###############################################################
#  Generated by:      Cadence Innovus 21.13-s100_1
#  OS:                Linux x86_64(Host ID acf3030)
#  Generated on:      Thu Oct 27 19:12:06 2022
#  Design:            b14
#  Command:           write_lef_abstract ./pnr_out/b14.pnr.lef
###############################################################

VERSION 5.8 ;

BUSBITCHARS "[]" ;
DIVIDERCHAR "/" ;

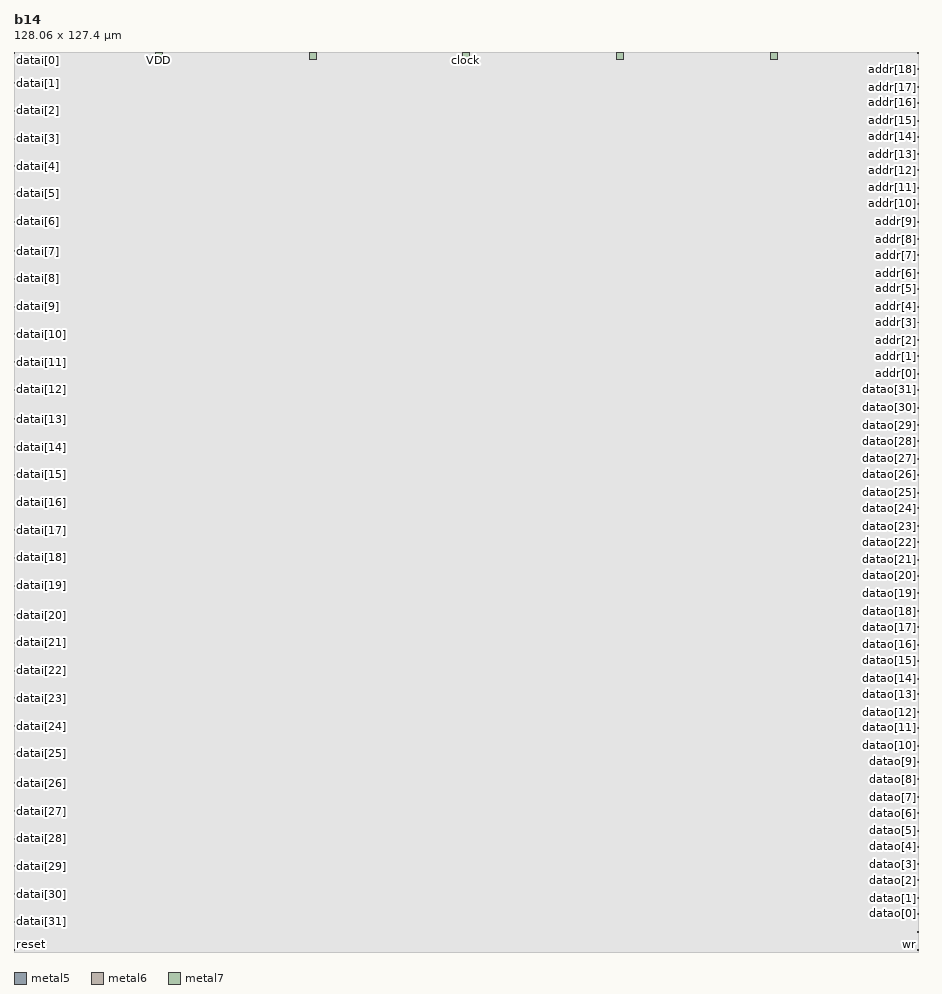
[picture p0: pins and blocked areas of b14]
MACRO b14
  CLASS BLOCK ;
  SIZE 128.060000 BY 127.400000 ;
  FOREIGN b14 0.000000 0.000000 ;
  ORIGIN 0 0 ;
  SYMMETRY X Y R90 ;
  PIN clock
    DIRECTION INPUT ;
    USE CLOCK ;
    PORT
      LAYER metal5 ;
        RECT 63.865000 127.260000 64.005000 127.400000 ;
    END
  END clock
  PIN reset
    DIRECTION INPUT ;
    USE SIGNAL ;
    PORT
      LAYER metal6 ;
        RECT 0.000000 0.280000 0.140000 0.420000 ;
    END
  END reset
  PIN addr[19]
    DIRECTION OUTPUT ;
    USE SIGNAL ;
    PORT
      LAYER metal6 ;
        RECT 127.920000 127.120000 128.060000 127.260000 ;
    END
  END addr[19]
  PIN addr[18]
    DIRECTION OUTPUT ;
    USE SIGNAL ;
    PORT
      LAYER metal6 ;
        RECT 127.920000 124.880000 128.060000 125.020000 ;
    END
  END addr[18]
  PIN addr[17]
    DIRECTION OUTPUT ;
    USE SIGNAL ;
    PORT
      LAYER metal6 ;
        RECT 127.920000 122.360000 128.060000 122.500000 ;
    END
  END addr[17]
  PIN addr[16]
    DIRECTION OUTPUT ;
    USE SIGNAL ;
    PORT
      LAYER metal6 ;
        RECT 127.920000 120.120000 128.060000 120.260000 ;
    END
  END addr[16]
  PIN addr[15]
    DIRECTION OUTPUT ;
    USE SIGNAL ;
    PORT
      LAYER metal6 ;
        RECT 127.920000 117.600000 128.060000 117.740000 ;
    END
  END addr[15]
  PIN addr[14]
    DIRECTION OUTPUT ;
    USE SIGNAL ;
    PORT
      LAYER metal6 ;
        RECT 127.920000 115.360000 128.060000 115.500000 ;
    END
  END addr[14]
  PIN addr[13]
    DIRECTION OUTPUT ;
    USE SIGNAL ;
    PORT
      LAYER metal6 ;
        RECT 127.920000 112.840000 128.060000 112.980000 ;
    END
  END addr[13]
  PIN addr[12]
    DIRECTION OUTPUT ;
    USE SIGNAL ;
    PORT
      LAYER metal6 ;
        RECT 127.920000 110.600000 128.060000 110.740000 ;
    END
  END addr[12]
  PIN addr[11]
    DIRECTION OUTPUT ;
    USE SIGNAL ;
    PORT
      LAYER metal6 ;
        RECT 127.920000 108.080000 128.060000 108.220000 ;
    END
  END addr[11]
  PIN addr[10]
    DIRECTION OUTPUT ;
    USE SIGNAL ;
    PORT
      LAYER metal6 ;
        RECT 127.920000 105.840000 128.060000 105.980000 ;
    END
  END addr[10]
  PIN addr[9]
    DIRECTION OUTPUT ;
    USE SIGNAL ;
    PORT
      LAYER metal6 ;
        RECT 127.920000 103.320000 128.060000 103.460000 ;
    END
  END addr[9]
  PIN addr[8]
    DIRECTION OUTPUT ;
    USE SIGNAL ;
    PORT
      LAYER metal6 ;
        RECT 127.920000 100.800000 128.060000 100.940000 ;
    END
  END addr[8]
  PIN addr[7]
    DIRECTION OUTPUT ;
    USE SIGNAL ;
    PORT
      LAYER metal6 ;
        RECT 127.920000 98.560000 128.060000 98.700000 ;
    END
  END addr[7]
  PIN addr[6]
    DIRECTION OUTPUT ;
    USE SIGNAL ;
    PORT
      LAYER metal6 ;
        RECT 127.920000 96.040000 128.060000 96.180000 ;
    END
  END addr[6]
  PIN addr[5]
    DIRECTION OUTPUT ;
    USE SIGNAL ;
    PORT
      LAYER metal6 ;
        RECT 127.920000 93.800000 128.060000 93.940000 ;
    END
  END addr[5]
  PIN addr[4]
    DIRECTION OUTPUT ;
    USE SIGNAL ;
    PORT
      LAYER metal6 ;
        RECT 127.920000 91.280000 128.060000 91.420000 ;
    END
  END addr[4]
  PIN addr[3]
    DIRECTION OUTPUT ;
    USE SIGNAL ;
    PORT
      LAYER metal6 ;
        RECT 127.920000 89.040000 128.060000 89.180000 ;
    END
  END addr[3]
  PIN addr[2]
    DIRECTION OUTPUT ;
    USE SIGNAL ;
    PORT
      LAYER metal6 ;
        RECT 127.920000 86.520000 128.060000 86.660000 ;
    END
  END addr[2]
  PIN addr[1]
    DIRECTION OUTPUT ;
    USE SIGNAL ;
    PORT
      LAYER metal6 ;
        RECT 127.920000 84.280000 128.060000 84.420000 ;
    END
  END addr[1]
  PIN addr[0]
    DIRECTION OUTPUT ;
    USE SIGNAL ;
    PORT
      LAYER metal6 ;
        RECT 127.920000 81.760000 128.060000 81.900000 ;
    END
  END addr[0]
  PIN datai[31]
    DIRECTION INPUT ;
    USE SIGNAL ;
    PORT
      LAYER metal6 ;
        RECT 0.000000 4.200000 0.140000 4.340000 ;
    END
  END datai[31]
  PIN datai[30]
    DIRECTION INPUT ;
    USE SIGNAL ;
    PORT
      LAYER metal6 ;
        RECT 0.000000 8.120000 0.140000 8.260000 ;
    END
  END datai[30]
  PIN datai[29]
    DIRECTION INPUT ;
    USE SIGNAL ;
    PORT
      LAYER metal6 ;
        RECT 0.000000 12.040000 0.140000 12.180000 ;
    END
  END datai[29]
  PIN datai[28]
    DIRECTION INPUT ;
    USE SIGNAL ;
    PORT
      LAYER metal6 ;
        RECT 0.000000 15.960000 0.140000 16.100000 ;
    END
  END datai[28]
  PIN datai[27]
    DIRECTION INPUT ;
    USE SIGNAL ;
    PORT
      LAYER metal6 ;
        RECT 0.000000 19.880000 0.140000 20.020000 ;
    END
  END datai[27]
  PIN datai[26]
    DIRECTION INPUT ;
    USE SIGNAL ;
    PORT
      LAYER metal6 ;
        RECT 0.000000 23.800000 0.140000 23.940000 ;
    END
  END datai[26]
  PIN datai[25]
    DIRECTION INPUT ;
    USE SIGNAL ;
    PORT
      LAYER metal6 ;
        RECT 0.000000 28.000000 0.140000 28.140000 ;
    END
  END datai[25]
  PIN datai[24]
    DIRECTION INPUT ;
    USE SIGNAL ;
    PORT
      LAYER metal6 ;
        RECT 0.000000 31.920000 0.140000 32.060000 ;
    END
  END datai[24]
  PIN datai[23]
    DIRECTION INPUT ;
    USE SIGNAL ;
    PORT
      LAYER metal6 ;
        RECT 0.000000 35.840000 0.140000 35.980000 ;
    END
  END datai[23]
  PIN datai[22]
    DIRECTION INPUT ;
    USE SIGNAL ;
    PORT
      LAYER metal6 ;
        RECT 0.000000 39.760000 0.140000 39.900000 ;
    END
  END datai[22]
  PIN datai[21]
    DIRECTION INPUT ;
    USE SIGNAL ;
    PORT
      LAYER metal6 ;
        RECT 0.000000 43.680000 0.140000 43.820000 ;
    END
  END datai[21]
  PIN datai[20]
    DIRECTION INPUT ;
    USE SIGNAL ;
    PORT
      LAYER metal6 ;
        RECT 0.000000 47.600000 0.140000 47.740000 ;
    END
  END datai[20]
  PIN datai[19]
    DIRECTION INPUT ;
    USE SIGNAL ;
    PORT
      LAYER metal6 ;
        RECT 0.000000 51.800000 0.140000 51.940000 ;
    END
  END datai[19]
  PIN datai[18]
    DIRECTION INPUT ;
    USE SIGNAL ;
    PORT
      LAYER metal6 ;
        RECT 0.000000 55.720000 0.140000 55.860000 ;
    END
  END datai[18]
  PIN datai[17]
    DIRECTION INPUT ;
    USE SIGNAL ;
    PORT
      LAYER metal6 ;
        RECT 0.000000 59.640000 0.140000 59.780000 ;
    END
  END datai[17]
  PIN datai[16]
    DIRECTION INPUT ;
    USE SIGNAL ;
    PORT
      LAYER metal6 ;
        RECT 0.000000 63.560000 0.140000 63.700000 ;
    END
  END datai[16]
  PIN datai[15]
    DIRECTION INPUT ;
    USE SIGNAL ;
    PORT
      LAYER metal6 ;
        RECT 0.000000 67.480000 0.140000 67.620000 ;
    END
  END datai[15]
  PIN datai[14]
    DIRECTION INPUT ;
    USE SIGNAL ;
    PORT
      LAYER metal6 ;
        RECT 0.000000 71.400000 0.140000 71.540000 ;
    END
  END datai[14]
  PIN datai[13]
    DIRECTION INPUT ;
    USE SIGNAL ;
    PORT
      LAYER metal6 ;
        RECT 0.000000 75.320000 0.140000 75.460000 ;
    END
  END datai[13]
  PIN datai[12]
    DIRECTION INPUT ;
    USE SIGNAL ;
    PORT
      LAYER metal6 ;
        RECT 0.000000 79.520000 0.140000 79.660000 ;
    END
  END datai[12]
  PIN datai[11]
    DIRECTION INPUT ;
    USE SIGNAL ;
    PORT
      LAYER metal6 ;
        RECT 0.000000 83.440000 0.140000 83.580000 ;
    END
  END datai[11]
  PIN datai[10]
    DIRECTION INPUT ;
    USE SIGNAL ;
    PORT
      LAYER metal6 ;
        RECT 0.000000 87.360000 0.140000 87.500000 ;
    END
  END datai[10]
  PIN datai[9]
    DIRECTION INPUT ;
    USE SIGNAL ;
    PORT
      LAYER metal6 ;
        RECT 0.000000 91.280000 0.140000 91.420000 ;
    END
  END datai[9]
  PIN datai[8]
    DIRECTION INPUT ;
    USE SIGNAL ;
    PORT
      LAYER metal6 ;
        RECT 0.000000 95.200000 0.140000 95.340000 ;
    END
  END datai[8]
  PIN datai[7]
    DIRECTION INPUT ;
    USE SIGNAL ;
    PORT
      LAYER metal6 ;
        RECT 0.000000 99.120000 0.140000 99.260000 ;
    END
  END datai[7]
  PIN datai[6]
    DIRECTION INPUT ;
    USE SIGNAL ;
    PORT
      LAYER metal6 ;
        RECT 0.000000 103.320000 0.140000 103.460000 ;
    END
  END datai[6]
  PIN datai[5]
    DIRECTION INPUT ;
    USE SIGNAL ;
    PORT
      LAYER metal6 ;
        RECT 0.000000 107.240000 0.140000 107.380000 ;
    END
  END datai[5]
  PIN datai[4]
    DIRECTION INPUT ;
    USE SIGNAL ;
    PORT
      LAYER metal6 ;
        RECT 0.000000 111.160000 0.140000 111.300000 ;
    END
  END datai[4]
  PIN datai[3]
    DIRECTION INPUT ;
    USE SIGNAL ;
    PORT
      LAYER metal6 ;
        RECT 0.000000 115.080000 0.140000 115.220000 ;
    END
  END datai[3]
  PIN datai[2]
    DIRECTION INPUT ;
    USE SIGNAL ;
    PORT
      LAYER metal6 ;
        RECT 0.000000 119.000000 0.140000 119.140000 ;
    END
  END datai[2]
  PIN datai[1]
    DIRECTION INPUT ;
    USE SIGNAL ;
    PORT
      LAYER metal6 ;
        RECT 0.000000 122.920000 0.140000 123.060000 ;
    END
  END datai[1]
  PIN datai[0]
    DIRECTION INPUT ;
    USE SIGNAL ;
    PORT
      LAYER metal6 ;
        RECT 0.000000 127.120000 0.140000 127.260000 ;
    END
  END datai[0]
  PIN datao[31]
    DIRECTION OUTPUT ;
    USE SIGNAL ;
    PORT
      LAYER metal6 ;
        RECT 127.920000 79.520000 128.060000 79.660000 ;
    END
  END datao[31]
  PIN datao[30]
    DIRECTION OUTPUT ;
    USE SIGNAL ;
    PORT
      LAYER metal6 ;
        RECT 127.920000 77.000000 128.060000 77.140000 ;
    END
  END datao[30]
  PIN datao[29]
    DIRECTION OUTPUT ;
    USE SIGNAL ;
    PORT
      LAYER metal6 ;
        RECT 127.920000 74.480000 128.060000 74.620000 ;
    END
  END datao[29]
  PIN datao[28]
    DIRECTION OUTPUT ;
    USE SIGNAL ;
    PORT
      LAYER metal6 ;
        RECT 127.920000 72.240000 128.060000 72.380000 ;
    END
  END datao[28]
  PIN datao[27]
    DIRECTION OUTPUT ;
    USE SIGNAL ;
    PORT
      LAYER metal6 ;
        RECT 127.920000 69.720000 128.060000 69.860000 ;
    END
  END datao[27]
  PIN datao[26]
    DIRECTION OUTPUT ;
    USE SIGNAL ;
    PORT
      LAYER metal6 ;
        RECT 127.920000 67.480000 128.060000 67.620000 ;
    END
  END datao[26]
  PIN datao[25]
    DIRECTION OUTPUT ;
    USE SIGNAL ;
    PORT
      LAYER metal6 ;
        RECT 127.920000 64.960000 128.060000 65.100000 ;
    END
  END datao[25]
  PIN datao[24]
    DIRECTION OUTPUT ;
    USE SIGNAL ;
    PORT
      LAYER metal6 ;
        RECT 127.920000 62.720000 128.060000 62.860000 ;
    END
  END datao[24]
  PIN datao[23]
    DIRECTION OUTPUT ;
    USE SIGNAL ;
    PORT
      LAYER metal6 ;
        RECT 127.920000 60.200000 128.060000 60.340000 ;
    END
  END datao[23]
  PIN datao[22]
    DIRECTION OUTPUT ;
    USE SIGNAL ;
    PORT
      LAYER metal6 ;
        RECT 127.920000 57.960000 128.060000 58.100000 ;
    END
  END datao[22]
  PIN datao[21]
    DIRECTION OUTPUT ;
    USE SIGNAL ;
    PORT
      LAYER metal6 ;
        RECT 127.920000 55.440000 128.060000 55.580000 ;
    END
  END datao[21]
  PIN datao[20]
    DIRECTION OUTPUT ;
    USE SIGNAL ;
    PORT
      LAYER metal6 ;
        RECT 127.920000 53.200000 128.060000 53.340000 ;
    END
  END datao[20]
  PIN datao[19]
    DIRECTION OUTPUT ;
    USE SIGNAL ;
    PORT
      LAYER metal6 ;
        RECT 127.920000 50.680000 128.060000 50.820000 ;
    END
  END datao[19]
  PIN datao[18]
    DIRECTION OUTPUT ;
    USE SIGNAL ;
    PORT
      LAYER metal6 ;
        RECT 127.920000 48.160000 128.060000 48.300000 ;
    END
  END datao[18]
  PIN datao[17]
    DIRECTION OUTPUT ;
    USE SIGNAL ;
    PORT
      LAYER metal6 ;
        RECT 127.920000 45.920000 128.060000 46.060000 ;
    END
  END datao[17]
  PIN datao[16]
    DIRECTION OUTPUT ;
    USE SIGNAL ;
    PORT
      LAYER metal6 ;
        RECT 127.920000 43.400000 128.060000 43.540000 ;
    END
  END datao[16]
  PIN datao[15]
    DIRECTION OUTPUT ;
    USE SIGNAL ;
    PORT
      LAYER metal6 ;
        RECT 127.920000 41.160000 128.060000 41.300000 ;
    END
  END datao[15]
  PIN datao[14]
    DIRECTION OUTPUT ;
    USE SIGNAL ;
    PORT
      LAYER metal6 ;
        RECT 127.920000 38.640000 128.060000 38.780000 ;
    END
  END datao[14]
  PIN datao[13]
    DIRECTION OUTPUT ;
    USE SIGNAL ;
    PORT
      LAYER metal6 ;
        RECT 127.920000 36.400000 128.060000 36.540000 ;
    END
  END datao[13]
  PIN datao[12]
    DIRECTION OUTPUT ;
    USE SIGNAL ;
    PORT
      LAYER metal6 ;
        RECT 127.920000 33.880000 128.060000 34.020000 ;
    END
  END datao[12]
  PIN datao[11]
    DIRECTION OUTPUT ;
    USE SIGNAL ;
    PORT
      LAYER metal6 ;
        RECT 127.920000 31.640000 128.060000 31.780000 ;
    END
  END datao[11]
  PIN datao[10]
    DIRECTION OUTPUT ;
    USE SIGNAL ;
    PORT
      LAYER metal6 ;
        RECT 127.920000 29.120000 128.060000 29.260000 ;
    END
  END datao[10]
  PIN datao[9]
    DIRECTION OUTPUT ;
    USE SIGNAL ;
    PORT
      LAYER metal6 ;
        RECT 127.920000 26.880000 128.060000 27.020000 ;
    END
  END datao[9]
  PIN datao[8]
    DIRECTION OUTPUT ;
    USE SIGNAL ;
    PORT
      LAYER metal6 ;
        RECT 127.920000 24.360000 128.060000 24.500000 ;
    END
  END datao[8]
  PIN datao[7]
    DIRECTION OUTPUT ;
    USE SIGNAL ;
    PORT
      LAYER metal6 ;
        RECT 127.920000 21.840000 128.060000 21.980000 ;
    END
  END datao[7]
  PIN datao[6]
    DIRECTION OUTPUT ;
    USE SIGNAL ;
    PORT
      LAYER metal6 ;
        RECT 127.920000 19.600000 128.060000 19.740000 ;
    END
  END datao[6]
  PIN datao[5]
    DIRECTION OUTPUT ;
    USE SIGNAL ;
    PORT
      LAYER metal6 ;
        RECT 127.920000 17.080000 128.060000 17.220000 ;
    END
  END datao[5]
  PIN datao[4]
    DIRECTION OUTPUT ;
    USE SIGNAL ;
    PORT
      LAYER metal6 ;
        RECT 127.920000 14.840000 128.060000 14.980000 ;
    END
  END datao[4]
  PIN datao[3]
    DIRECTION OUTPUT ;
    USE SIGNAL ;
    PORT
      LAYER metal6 ;
        RECT 127.920000 12.320000 128.060000 12.460000 ;
    END
  END datao[3]
  PIN datao[2]
    DIRECTION OUTPUT ;
    USE SIGNAL ;
    PORT
      LAYER metal6 ;
        RECT 127.920000 10.080000 128.060000 10.220000 ;
    END
  END datao[2]
  PIN datao[1]
    DIRECTION OUTPUT ;
    USE SIGNAL ;
    PORT
      LAYER metal6 ;
        RECT 127.920000 7.560000 128.060000 7.700000 ;
    END
  END datao[1]
  PIN datao[0]
    DIRECTION OUTPUT ;
    USE SIGNAL ;
    PORT
      LAYER metal6 ;
        RECT 127.920000 5.320000 128.060000 5.460000 ;
    END
  END datao[0]
  PIN rd
    DIRECTION OUTPUT ;
    USE SIGNAL ;
    PORT
      LAYER metal6 ;
        RECT 127.920000 2.800000 128.060000 2.940000 ;
    END
  END rd
  PIN wr
    DIRECTION OUTPUT ;
    USE SIGNAL ;
    PORT
      LAYER metal6 ;
        RECT 127.920000 0.280000 128.060000 0.420000 ;
    END
  END wr
  PIN VDD
    DIRECTION INOUT ;
    USE POWER ;
    PORT
      LAYER metal7 ;
        RECT 20.000000 126.400000 21.000000 127.400000 ;
    END
    PORT
      LAYER metal7 ;
        RECT 41.765000 126.400000 42.765000 127.400000 ;
    END
    PORT
      LAYER metal7 ;
        RECT 63.530000 126.400000 64.530000 127.400000 ;
    END
    PORT
      LAYER metal7 ;
        RECT 85.295000 126.400000 86.295000 127.400000 ;
    END
    PORT
      LAYER metal7 ;
        RECT 107.060000 126.400000 108.060000 127.400000 ;
    END
  END VDD
  OBS
    LAYER metal1 ;
      RECT 0.000000 0.000000 128.060000 127.400000 ;
    LAYER metal2 ;
      RECT 0.000000 0.000000 128.060000 127.400000 ;
    LAYER metal3 ;
      RECT 0.000000 0.000000 128.060000 127.400000 ;
    LAYER metal4 ;
      RECT 0.000000 0.000000 128.060000 127.400000 ;
    LAYER metal5 ;
      RECT 64.145000 127.120000 128.060000 127.400000 ;
      RECT 0.000000 127.120000 63.725000 127.400000 ;
      RECT 0.000000 0.000000 128.060000 127.120000 ;
    LAYER metal6 ;
      RECT 0.280000 126.980000 127.780000 127.400000 ;
      RECT 0.000000 125.160000 128.060000 126.980000 ;
      RECT 0.000000 124.740000 127.780000 125.160000 ;
      RECT 0.000000 123.200000 128.060000 124.740000 ;
      RECT 0.280000 122.780000 128.060000 123.200000 ;
      RECT 0.000000 122.640000 128.060000 122.780000 ;
      RECT 0.000000 122.220000 127.780000 122.640000 ;
      RECT 0.000000 120.400000 128.060000 122.220000 ;
      RECT 0.000000 119.980000 127.780000 120.400000 ;
      RECT 0.000000 119.280000 128.060000 119.980000 ;
      RECT 0.280000 118.860000 128.060000 119.280000 ;
      RECT 0.000000 117.880000 128.060000 118.860000 ;
      RECT 0.000000 117.460000 127.780000 117.880000 ;
      RECT 0.000000 115.640000 128.060000 117.460000 ;
      RECT 0.000000 115.360000 127.780000 115.640000 ;
      RECT 0.280000 115.220000 127.780000 115.360000 ;
      RECT 0.280000 114.940000 128.060000 115.220000 ;
      RECT 0.000000 113.120000 128.060000 114.940000 ;
      RECT 0.000000 112.700000 127.780000 113.120000 ;
      RECT 0.000000 111.440000 128.060000 112.700000 ;
      RECT 0.280000 111.020000 128.060000 111.440000 ;
      RECT 0.000000 110.880000 128.060000 111.020000 ;
      RECT 0.000000 110.460000 127.780000 110.880000 ;
      RECT 0.000000 108.360000 128.060000 110.460000 ;
      RECT 0.000000 107.940000 127.780000 108.360000 ;
      RECT 0.000000 107.520000 128.060000 107.940000 ;
      RECT 0.280000 107.100000 128.060000 107.520000 ;
      RECT 0.000000 106.120000 128.060000 107.100000 ;
      RECT 0.000000 105.700000 127.780000 106.120000 ;
      RECT 0.000000 103.600000 128.060000 105.700000 ;
      RECT 0.280000 103.180000 127.780000 103.600000 ;
      RECT 0.000000 101.080000 128.060000 103.180000 ;
      RECT 0.000000 100.660000 127.780000 101.080000 ;
      RECT 0.000000 99.400000 128.060000 100.660000 ;
      RECT 0.280000 98.980000 128.060000 99.400000 ;
      RECT 0.000000 98.840000 128.060000 98.980000 ;
      RECT 0.000000 98.420000 127.780000 98.840000 ;
      RECT 0.000000 96.320000 128.060000 98.420000 ;
      RECT 0.000000 95.900000 127.780000 96.320000 ;
      RECT 0.000000 95.480000 128.060000 95.900000 ;
      RECT 0.280000 95.060000 128.060000 95.480000 ;
      RECT 0.000000 94.080000 128.060000 95.060000 ;
      RECT 0.000000 93.660000 127.780000 94.080000 ;
      RECT 0.000000 91.560000 128.060000 93.660000 ;
      RECT 0.280000 91.140000 127.780000 91.560000 ;
      RECT 0.000000 89.320000 128.060000 91.140000 ;
      RECT 0.000000 88.900000 127.780000 89.320000 ;
      RECT 0.000000 87.640000 128.060000 88.900000 ;
      RECT 0.280000 87.220000 128.060000 87.640000 ;
      RECT 0.000000 86.800000 128.060000 87.220000 ;
      RECT 0.000000 86.380000 127.780000 86.800000 ;
      RECT 0.000000 84.560000 128.060000 86.380000 ;
      RECT 0.000000 84.140000 127.780000 84.560000 ;
      RECT 0.000000 83.720000 128.060000 84.140000 ;
      RECT 0.280000 83.300000 128.060000 83.720000 ;
      RECT 0.000000 82.040000 128.060000 83.300000 ;
      RECT 0.000000 81.620000 127.780000 82.040000 ;
      RECT 0.000000 79.800000 128.060000 81.620000 ;
      RECT 0.280000 79.380000 127.780000 79.800000 ;
      RECT 0.000000 77.280000 128.060000 79.380000 ;
      RECT 0.000000 76.860000 127.780000 77.280000 ;
      RECT 0.000000 75.600000 128.060000 76.860000 ;
      RECT 0.280000 75.180000 128.060000 75.600000 ;
      RECT 0.000000 74.760000 128.060000 75.180000 ;
      RECT 0.000000 74.340000 127.780000 74.760000 ;
      RECT 0.000000 72.520000 128.060000 74.340000 ;
      RECT 0.000000 72.100000 127.780000 72.520000 ;
      RECT 0.000000 71.680000 128.060000 72.100000 ;
      RECT 0.280000 71.260000 128.060000 71.680000 ;
      RECT 0.000000 70.000000 128.060000 71.260000 ;
      RECT 0.000000 69.580000 127.780000 70.000000 ;
      RECT 0.000000 67.760000 128.060000 69.580000 ;
      RECT 0.280000 67.340000 127.780000 67.760000 ;
      RECT 0.000000 65.240000 128.060000 67.340000 ;
      RECT 0.000000 64.820000 127.780000 65.240000 ;
      RECT 0.000000 63.840000 128.060000 64.820000 ;
      RECT 0.280000 63.420000 128.060000 63.840000 ;
      RECT 0.000000 63.000000 128.060000 63.420000 ;
      RECT 0.000000 62.580000 127.780000 63.000000 ;
      RECT 0.000000 60.480000 128.060000 62.580000 ;
      RECT 0.000000 60.060000 127.780000 60.480000 ;
      RECT 0.000000 59.920000 128.060000 60.060000 ;
      RECT 0.280000 59.500000 128.060000 59.920000 ;
      RECT 0.000000 58.240000 128.060000 59.500000 ;
      RECT 0.000000 57.820000 127.780000 58.240000 ;
      RECT 0.000000 56.000000 128.060000 57.820000 ;
      RECT 0.280000 55.720000 128.060000 56.000000 ;
      RECT 0.280000 55.580000 127.780000 55.720000 ;
      RECT 0.000000 55.300000 127.780000 55.580000 ;
      RECT 0.000000 53.480000 128.060000 55.300000 ;
      RECT 0.000000 53.060000 127.780000 53.480000 ;
      RECT 0.000000 52.080000 128.060000 53.060000 ;
      RECT 0.280000 51.660000 128.060000 52.080000 ;
      RECT 0.000000 50.960000 128.060000 51.660000 ;
      RECT 0.000000 50.540000 127.780000 50.960000 ;
      RECT 0.000000 48.440000 128.060000 50.540000 ;
      RECT 0.000000 48.020000 127.780000 48.440000 ;
      RECT 0.000000 47.880000 128.060000 48.020000 ;
      RECT 0.280000 47.460000 128.060000 47.880000 ;
      RECT 0.000000 46.200000 128.060000 47.460000 ;
      RECT 0.000000 45.780000 127.780000 46.200000 ;
      RECT 0.000000 43.960000 128.060000 45.780000 ;
      RECT 0.280000 43.680000 128.060000 43.960000 ;
      RECT 0.280000 43.540000 127.780000 43.680000 ;
      RECT 0.000000 43.260000 127.780000 43.540000 ;
      RECT 0.000000 41.440000 128.060000 43.260000 ;
      RECT 0.000000 41.020000 127.780000 41.440000 ;
      RECT 0.000000 40.040000 128.060000 41.020000 ;
      RECT 0.280000 39.620000 128.060000 40.040000 ;
      RECT 0.000000 38.920000 128.060000 39.620000 ;
      RECT 0.000000 38.500000 127.780000 38.920000 ;
      RECT 0.000000 36.680000 128.060000 38.500000 ;
      RECT 0.000000 36.260000 127.780000 36.680000 ;
      RECT 0.000000 36.120000 128.060000 36.260000 ;
      RECT 0.280000 35.700000 128.060000 36.120000 ;
      RECT 0.000000 34.160000 128.060000 35.700000 ;
      RECT 0.000000 33.740000 127.780000 34.160000 ;
      RECT 0.000000 32.200000 128.060000 33.740000 ;
      RECT 0.280000 31.920000 128.060000 32.200000 ;
      RECT 0.280000 31.780000 127.780000 31.920000 ;
      RECT 0.000000 31.500000 127.780000 31.780000 ;
      RECT 0.000000 29.400000 128.060000 31.500000 ;
      RECT 0.000000 28.980000 127.780000 29.400000 ;
      RECT 0.000000 28.280000 128.060000 28.980000 ;
      RECT 0.280000 27.860000 128.060000 28.280000 ;
      RECT 0.000000 27.160000 128.060000 27.860000 ;
      RECT 0.000000 26.740000 127.780000 27.160000 ;
      RECT 0.000000 24.640000 128.060000 26.740000 ;
      RECT 0.000000 24.220000 127.780000 24.640000 ;
      RECT 0.000000 24.080000 128.060000 24.220000 ;
      RECT 0.280000 23.660000 128.060000 24.080000 ;
      RECT 0.000000 22.120000 128.060000 23.660000 ;
      RECT 0.000000 21.700000 127.780000 22.120000 ;
      RECT 0.000000 20.160000 128.060000 21.700000 ;
      RECT 0.280000 19.880000 128.060000 20.160000 ;
      RECT 0.280000 19.740000 127.780000 19.880000 ;
      RECT 0.000000 19.460000 127.780000 19.740000 ;
      RECT 0.000000 17.360000 128.060000 19.460000 ;
      RECT 0.000000 16.940000 127.780000 17.360000 ;
      RECT 0.000000 16.240000 128.060000 16.940000 ;
      RECT 0.280000 15.820000 128.060000 16.240000 ;
      RECT 0.000000 15.120000 128.060000 15.820000 ;
      RECT 0.000000 14.700000 127.780000 15.120000 ;
      RECT 0.000000 12.600000 128.060000 14.700000 ;
      RECT 0.000000 12.320000 127.780000 12.600000 ;
      RECT 0.280000 12.180000 127.780000 12.320000 ;
      RECT 0.280000 11.900000 128.060000 12.180000 ;
      RECT 0.000000 10.360000 128.060000 11.900000 ;
      RECT 0.000000 9.940000 127.780000 10.360000 ;
      RECT 0.000000 8.400000 128.060000 9.940000 ;
      RECT 0.280000 7.980000 128.060000 8.400000 ;
      RECT 0.000000 7.840000 128.060000 7.980000 ;
      RECT 0.000000 7.420000 127.780000 7.840000 ;
      RECT 0.000000 5.600000 128.060000 7.420000 ;
      RECT 0.000000 5.180000 127.780000 5.600000 ;
      RECT 0.000000 4.480000 128.060000 5.180000 ;
      RECT 0.280000 4.060000 128.060000 4.480000 ;
      RECT 0.000000 3.080000 128.060000 4.060000 ;
      RECT 0.000000 2.660000 127.780000 3.080000 ;
      RECT 0.000000 0.560000 128.060000 2.660000 ;
      RECT 0.280000 0.140000 127.780000 0.560000 ;
      RECT 0.000000 0.000000 128.060000 0.140000 ;
    LAYER metal7 ;
      RECT 108.960000 125.500000 128.060000 127.400000 ;
      RECT 87.195000 125.500000 106.160000 127.400000 ;
      RECT 65.430000 125.500000 84.395000 127.400000 ;
      RECT 43.665000 125.500000 62.630000 127.400000 ;
      RECT 21.900000 125.500000 40.865000 127.400000 ;
      RECT 0.000000 125.500000 19.100000 127.400000 ;
      RECT 0.000000 0.000000 128.060000 125.500000 ;
    LAYER metal8 ;
      RECT 0.000000 0.000000 128.060000 127.400000 ;
    LAYER metal9 ;
      RECT 0.000000 0.000000 128.060000 127.400000 ;
    LAYER metal10 ;
      RECT 0.000000 0.000000 128.060000 127.400000 ;
  END
END b14

END LIBRARY
